VERSION 5.8 ;
BUSBITCHARS "[]" ;
DIVIDERCHAR "/" ;
UNITS
    DATABASE MICRONS 1000 ;
END UNITS

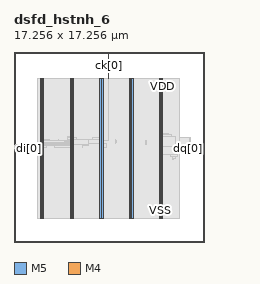
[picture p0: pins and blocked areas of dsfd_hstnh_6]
MACRO dsfd_hstnh_6
  FOREIGN dsfd_hstnh_6 0 0 ;
  CLASS BLOCK ;
  SIZE 17.256 BY 17.256 ;
  PIN ck[0]
    DIRECTION INPUT ;
    USE SIGNAL ;
    PORT
      LAYER M5 ;
        RECT  8.592 17.172 8.616 17.256 ;
    END
    PORT
      LAYER M5 ;
        RECT  8.592 14.873 8.616 17.232 ;
    END
  END ck[0]
  PIN di[0]
    DIRECTION INPUT ;
    USE SIGNAL ;
    PORT
      LAYER M4 ;
        RECT  0 8.496 0.084 8.52 ;
    END
  END di[0]
  PIN di[1]
    DIRECTION INPUT ;
    USE SIGNAL ;
    PORT
      LAYER M4 ;
        RECT  0 8.544 0.084 8.568 ;
    END
  END di[1]
  PIN di[2]
    DIRECTION INPUT ;
    USE SIGNAL ;
    PORT
      LAYER M4 ;
        RECT  0 8.592 0.084 8.616 ;
    END
  END di[2]
  PIN di[3]
    DIRECTION INPUT ;
    USE SIGNAL ;
    PORT
      LAYER M4 ;
        RECT  0 8.64 0.084 8.664 ;
    END
  END di[3]
  PIN di[4]
    DIRECTION INPUT ;
    USE SIGNAL ;
    PORT
      LAYER M4 ;
        RECT  0 8.688 0.084 8.712 ;
    END
  END di[4]
  PIN di[5]
    DIRECTION INPUT ;
    USE SIGNAL ;
    PORT
      LAYER M4 ;
        RECT  0 8.736 0.084 8.76 ;
    END
  END di[5]
  PIN dq[0]
    DIRECTION OUTPUT ;
    USE SIGNAL ;
    PORT
      LAYER M4 ;
        RECT  17.172 8.496 17.256 8.52 ;
    END
  END dq[0]
  PIN dq[1]
    DIRECTION OUTPUT ;
    USE SIGNAL ;
    PORT
      LAYER M4 ;
        RECT  17.172 8.544 17.256 8.568 ;
    END
  END dq[1]
  PIN dq[2]
    DIRECTION OUTPUT ;
    USE SIGNAL ;
    PORT
      LAYER M4 ;
        RECT  17.172 8.592 17.256 8.616 ;
    END
  END dq[2]
  PIN dq[3]
    DIRECTION OUTPUT ;
    USE SIGNAL ;
    PORT
      LAYER M4 ;
        RECT  17.172 8.64 17.256 8.664 ;
    END
  END dq[3]
  PIN dq[4]
    DIRECTION OUTPUT ;
    USE SIGNAL ;
    PORT
      LAYER M4 ;
        RECT  17.172 8.688 17.256 8.712 ;
    END
  END dq[4]
  PIN dq[5]
    DIRECTION OUTPUT ;
    USE SIGNAL ;
    PORT
      LAYER M4 ;
        RECT  17.172 8.736 17.256 8.76 ;
    END
  END dq[5]
  PIN VDD
    DIRECTION INOUT ;
    USE POWER ;
    PORT
      LAYER M5 ;
        RECT  13.392 2.151 13.512 14.873 ;
        RECT  10.692 2.151 10.812 14.873 ;
        RECT  7.992 2.151 8.112 14.873 ;
        RECT  5.292 2.151 5.412 14.873 ;
        RECT  2.592 2.151 2.712 14.873 ;
    END
  END VDD
  PIN VSS
    DIRECTION INOUT ;
    USE GROUND ;
    PORT
      LAYER M5 ;
        RECT  13.2 2.137 13.32 14.859 ;
        RECT  10.5 2.137 10.62 14.859 ;
        RECT  7.8 2.137 7.92 14.859 ;
        RECT  5.1 2.137 5.22 14.859 ;
        RECT  2.4 2.137 2.52 14.859 ;
    END
  END VSS
  # OT_OBS_CLOSED layer=M5 d_um=1.536 added=0
  OBS
    LAYER RVTN ;
     RECT  2.16 2.16 15.066 2.295 ;
     RECT  2.16 2.565 15.066 2.835 ;
     RECT  2.16 3.105 15.066 3.375 ;
     RECT  2.16 3.645 15.066 3.915 ;
     RECT  2.16 4.185 15.066 4.455 ;
     RECT  2.16 4.725 15.066 4.995 ;
     RECT  2.16 5.265 15.066 5.535 ;
     RECT  2.16 5.805 15.066 6.075 ;
     RECT  2.16 6.345 15.066 6.615 ;
     RECT  2.16 6.885 15.066 7.155 ;
     RECT  2.16 7.425 15.066 7.695 ;
     RECT  2.16 7.965 15.066 8.235 ;
     RECT  2.16 8.505 15.066 8.775 ;
     RECT  2.16 9.045 15.066 9.315 ;
     RECT  2.16 9.585 15.066 9.855 ;
     RECT  2.16 10.125 15.066 10.395 ;
     RECT  2.16 10.665 15.066 10.935 ;
     RECT  2.16 11.205 15.066 11.475 ;
     RECT  2.16 11.745 15.066 12.015 ;
     RECT  2.16 12.285 15.066 12.555 ;
     RECT  2.16 12.825 15.066 13.095 ;
     RECT  2.16 13.365 15.066 13.635 ;
     RECT  2.16 13.905 15.066 14.175 ;
     RECT  2.16 14.445 15.066 14.715 ;
    LAYER RVTP ;
     RECT  2.16 2.295 15.066 2.565 ;
     RECT  2.16 2.835 15.066 3.105 ;
     RECT  2.16 3.375 15.066 3.645 ;
     RECT  2.16 3.915 15.066 4.185 ;
     RECT  2.16 4.455 15.066 4.725 ;
     RECT  2.16 4.995 15.066 5.265 ;
     RECT  2.16 5.535 15.066 5.805 ;
     RECT  2.16 6.075 15.066 6.345 ;
     RECT  2.16 6.615 15.066 6.885 ;
     RECT  2.16 7.155 15.066 7.425 ;
     RECT  2.16 7.695 15.066 7.965 ;
     RECT  2.16 8.235 15.066 8.505 ;
     RECT  2.16 8.775 15.066 9.045 ;
     RECT  2.16 9.315 15.066 9.585 ;
     RECT  2.16 9.855 15.066 10.125 ;
     RECT  2.16 10.395 15.066 10.665 ;
     RECT  2.16 10.935 15.066 11.205 ;
     RECT  2.16 11.475 15.066 11.745 ;
     RECT  2.16 12.015 15.066 12.285 ;
     RECT  2.16 12.555 15.066 12.825 ;
     RECT  2.16 13.095 15.066 13.365 ;
     RECT  2.16 13.635 15.066 13.905 ;
     RECT  2.16 14.175 15.066 14.445 ;
     RECT  2.16 14.715 15.066 14.85 ;
    LAYER M1 ;
     RECT  2.16 2.151 15.066 14.859 ;
    LAYER M2 ;
     RECT  0.139 8.514 0.283 8.532 ;
     RECT  0.283 8.28 2.16 8.532 ;
     RECT  2.16 2.151 15.066 14.859 ;
     RECT  15.066 8.316 15.971 9.504 ;
     RECT  15.971 9.486 16.007 9.504 ;
     RECT  15.971 8.406 16.547 8.424 ;
    LAYER M3 ;
     RECT  2.415 2.143 2.505 2.413 ;
     RECT  5.115 2.143 5.205 2.413 ;
     RECT  7.815 2.143 7.905 2.413 ;
     RECT  10.515 2.143 10.605 2.413 ;
     RECT  13.215 2.143 13.305 2.413 ;
     RECT  14.4 7.465 14.418 7.501 ;
     RECT  14.4 7.501 14.526 7.591 ;
     RECT  14.4 7.591 14.67 7.771 ;
     RECT  13.215 2.413 13.497 7.933 ;
     RECT  14.22 7.771 14.886 7.933 ;
     RECT  15.948 8.311 15.966 8.401 ;
     RECT  2.415 2.413 2.697 8.437 ;
     RECT  0.288 8.275 0.306 8.509 ;
     RECT  2.304 8.437 2.697 8.581 ;
     RECT  3.708 8.545 3.978 8.581 ;
     RECT  5.115 2.413 5.397 8.581 ;
     RECT  7.815 2.413 8.097 8.581 ;
     RECT  15.948 8.401 16.542 8.669 ;
     RECT  0.144 8.509 0.306 8.717 ;
     RECT  13.215 7.933 14.886 8.717 ;
     RECT  0.144 8.717 0.234 8.731 ;
     RECT  2.304 8.581 2.97 8.731 ;
     RECT  3.708 8.581 5.397 8.731 ;
     RECT  0.108 8.731 0.234 8.765 ;
     RECT  15.948 8.669 16.002 8.771 ;
     RECT  6.228 8.545 6.246 8.779 ;
     RECT  2.304 8.731 5.397 8.851 ;
     RECT  6.228 8.779 6.75 8.851 ;
     RECT  0.108 8.765 0.126 8.861 ;
     RECT  2.304 8.851 6.75 8.941 ;
     RECT  7.815 8.581 8.406 8.941 ;
     RECT  2.304 8.941 8.406 8.969 ;
     RECT  2.304 8.969 8.097 9.005 ;
     RECT  11.988 8.851 12.078 9.005 ;
     RECT  9.18 8.941 9.198 9.013 ;
     RECT  2.415 9.005 8.097 9.239 ;
     RECT  9.18 9.013 9.342 9.239 ;
     RECT  11.988 9.005 12.006 9.239 ;
     RECT  2.415 9.239 3.258 9.275 ;
     RECT  4.824 9.239 8.097 9.275 ;
     RECT  9.18 9.239 9.198 9.275 ;
     RECT  4.824 9.275 5.922 9.293 ;
     RECT  4.032 9.239 4.05 9.311 ;
     RECT  4.824 9.293 5.67 9.509 ;
     RECT  7.164 9.275 8.097 9.509 ;
     RECT  15.984 8.771 16.002 9.509 ;
     RECT  4.824 9.509 5.397 9.545 ;
     RECT  13.215 8.717 14.67 9.545 ;
     RECT  13.215 9.545 14.31 9.779 ;
     RECT  13.215 9.779 14.022 9.815 ;
     RECT  2.415 9.275 2.697 14.597 ;
     RECT  5.115 9.545 5.397 14.597 ;
     RECT  7.815 9.509 8.097 14.597 ;
     RECT  10.515 2.413 10.797 14.597 ;
     RECT  13.215 9.815 13.497 14.597 ;
     RECT  2.607 14.597 2.697 14.867 ;
     RECT  5.307 14.597 5.397 14.867 ;
     RECT  8.007 14.597 8.097 14.867 ;
     RECT  10.707 14.597 10.797 14.867 ;
     RECT  13.407 14.597 13.497 14.867 ;
    LAYER M4 ;
     RECT  0.06 8.496 0.097 8.76 ;
     RECT  0.097 8.496 2.408 8.856 ;
     RECT  2.408 2.148 2.512 14.592 ;
     RECT  2.512 2.418 2.6 14.592 ;
     RECT  2.6 2.418 2.704 14.862 ;
     RECT  2.704 8.736 3.269 8.76 ;
     RECT  3.697 9.024 4.097 9.048 ;
     RECT  4.597 9.072 5.108 9.096 ;
     RECT  5.108 2.148 5.212 14.592 ;
     RECT  5.212 2.418 5.3 14.592 ;
     RECT  5.3 2.418 5.404 14.862 ;
     RECT  5.404 8.88 6.725 9.288 ;
     RECT  6.725 8.976 7.808 9.288 ;
     RECT  7.808 2.148 7.912 14.592 ;
     RECT  7.912 2.418 8 14.592 ;
     RECT  8 2.418 8.104 14.862 ;
     RECT  8.104 9.264 8.627 9.288 ;
     RECT  10.508 2.148 10.612 14.592 ;
     RECT  10.612 2.418 10.7 14.592 ;
     RECT  10.7 2.418 10.804 14.862 ;
     RECT  13.208 2.148 13.312 14.592 ;
     RECT  13.312 2.418 13.4 14.592 ;
     RECT  13.4 2.418 13.504 14.862 ;
     RECT  14.497 8.544 14.857 8.568 ;
     RECT  14.857 8.544 15.937 8.712 ;
     RECT  15.937 8.496 17.196 8.76 ;
    LAYER M5 ;
     RECT  2.4 2.137 2.52 2.151 ;
     RECT  5.1 2.137 5.22 2.151 ;
     RECT  7.8 2.137 7.92 2.151 ;
     RECT  10.5 2.137 10.62 2.151 ;
     RECT  13.2 2.137 13.32 2.151 ;
     RECT  7.8 2.151 8.112 9.253 ;
     RECT  2.4 2.151 2.712 14.859 ;
     RECT  5.1 2.151 5.412 14.859 ;
     RECT  7.8 9.253 8.616 14.859 ;
     RECT  10.5 2.151 10.812 14.859 ;
     RECT  13.2 2.151 13.512 14.859 ;
     RECT  2.592 14.859 2.712 14.873 ;
     RECT  5.292 14.859 5.412 14.873 ;
     RECT  7.992 14.859 8.616 14.873 ;
     RECT  10.692 14.859 10.812 14.873 ;
     RECT  13.392 14.859 13.512 14.873 ;
  END
END dsfd_hstnh_6
END LIBRARY
